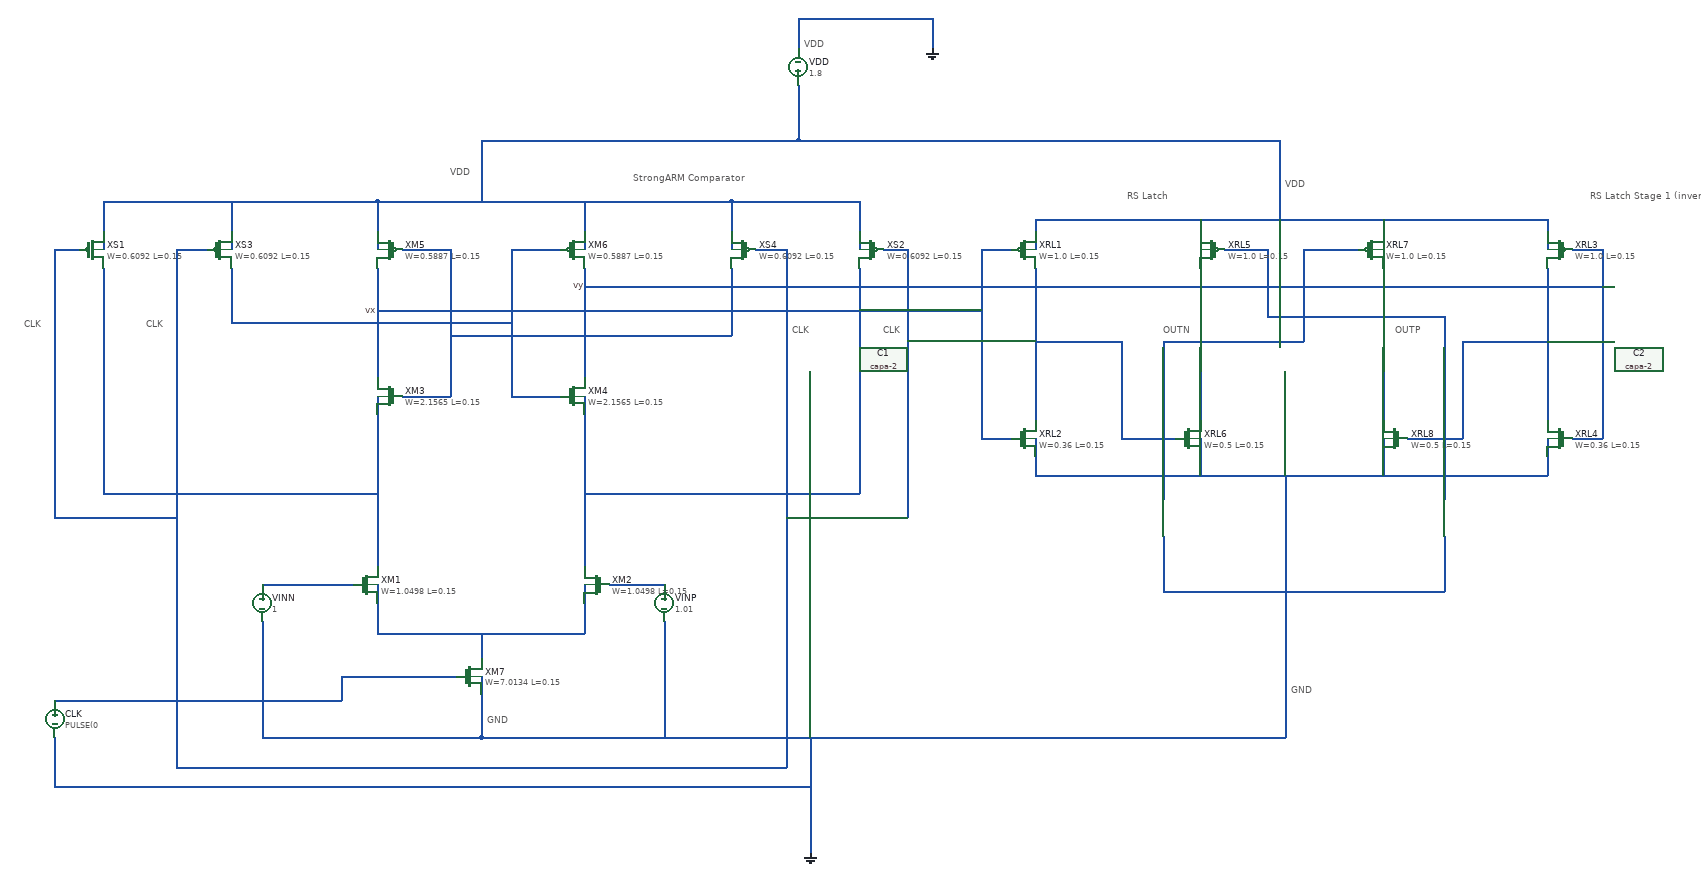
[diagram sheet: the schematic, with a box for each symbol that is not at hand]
v {xschem version=3.4.7 file_version=1.2}
G {}
K {}
V {}
S {}
E {}
T {StrongARM Comparator} -2230 -1580 0 0 0.4 0.4 {}
T {RS Latch } -1420 -1550 0 0 0.3 0.3 {}
T {RS Latch Stage 1 (inverters)} -660 -1550 0 1 0.3 0.3 {}
T {OUTN} -1360 -1330 0 0 0.4 0.4 {}
T {OUTP
} -980 -1330 0 0 0.4 0.4 {}
T {VDD} -1160 -1570 0 0 0.4 0.4 {}
T {GND} -1150 -740 0 0 0.4 0.4 {}
T {GND} -2470 -690 0 0 0.4 0.4 {}
T {CLK} -1970 -1330 0 0 0.4 0.4 {}
T {VDD} -1950 -1800 0 0 0.4 0.4 {}
T {CLK} -1820 -1330 0 0 0.4 0.4 {}
T {CLK} -3030 -1340 0 0 0.4 0.4 {}
T {CLK} -3230 -1340 0 0 0.4 0.4 {}
T {VDD} -2530 -1590 0 0 0.4 0.4 {}
N -3100 -1500 -3100 -1480 {lab=#net1}
N -3160 -1450 -3140 -1450 {lab=#net2}
N -3100 -1420 -3100 -1400 {lab=#net3}
N -2890 -1500 -2890 -1480 {lab=#net1}
N -2950 -1450 -2930 -1450 {lab=#net2}
N -2890 -1420 -2890 -1400 {lab=vx}
N -2610 -1450 -2590 -1450 {lab=vy}
N -2650 -1420 -2650 -1400 {lab=vx}
N -2650 -1260 -2650 -1240 {lab=vx}
N -2610 -1210 -2590 -1210 {lab=vy}
N -2650 -1180 -2650 -1160 {lab=#net3}
N -2650 -950 -2650 -930 {lab=#net3}
N -2650 -870 -2650 -850 {lab=#net4}
N -2480 -800 -2480 -780 {lab=#net4}
N -2540 -750 -2520 -750 {lab=#net2}
N -2480 -720 -2480 -700 {lab=GND}
N -1570 -1500 -1570 -1480 {lab=#net1}
N -1630 -1450 -1610 -1450 {lab=vx}
N -1570 -1420 -1570 -1400 {lab=#net5}
N -1570 -1190 -1570 -1170 {lab=#net5}
N -1630 -1140 -1610 -1140 {lab=vx}
N -1570 -1110 -1570 -1090 {lab=GND}
N -1300 -1180 -1300 -1160 {lab=#net6}
N -1300 -1100 -1300 -1080 {lab=GND}
N -1300 -1430 -1300 -1180 {lab=#net6}
N -1570 -1400 -1570 -1190 {lab=#net5}
N -1660 -1450 -1630 -1450 {lab=vx}
N -1660 -1450 -1660 -1140 {lab=vx}
N -1660 -1140 -1630 -1140 {lab=vx}
N -1430 -1140 -1340 -1140 {lab=#net5}
N -1430 -1300 -1430 -1140 {lab=#net5}
N -730 -1500 -730 -1480 {lab=#net1}
N -690 -1450 -670 -1450 {lab=vy}
N -730 -1420 -730 -1400 {lab=#net7}
N -730 -1190 -730 -1170 {lab=#net7}
N -690 -1140 -670 -1140 {lab=vy}
N -730 -1110 -730 -1090 {lab=GND}
N -1000 -1180 -1000 -1160 {lab=#net8}
N -1000 -1100 -1000 -1080 {lab=GND}
N -1000 -1430 -1000 -1180 {lab=#net8}
N -730 -1400 -730 -1190 {lab=#net7}
N -670 -1450 -640 -1450 {lab=vy}
N -640 -1450 -640 -1140 {lab=vy}
N -670 -1140 -640 -1140 {lab=vy}
N -870 -1300 -730 -1300 {lab=#net7}
N -960 -1140 -870 -1140 {lab=#net7}
N -870 -1300 -870 -1140 {lab=#net7}
N -1130 -1450 -1040 -1450 {lab=#net6}
N -1130 -1450 -1130 -1300 {lab=#net6}
N -1300 -1300 -1130 -1300 {lab=#net6}
N -1260 -1450 -1190 -1450 {lab=#net8}
N -1190 -1450 -1190 -1340 {lab=#net8}
N -1190 -1340 -1000 -1340 {lab=#net8}
N -1570 -1500 -730 -1500 {lab=#net1}
N -1000 -1500 -1000 -1480 {lab=#net1}
N -1300 -1500 -1300 -1480 {lab=#net1}
N -1570 -1090 -1570 -1080 {lab=GND}
N -1570 -1080 -730 -1080 {lab=GND}
N -730 -1090 -730 -1080 {lab=GND}
N -1000 -1110 -1000 -1100 {lab=GND}
N -1300 -1110 -1300 -1100 {lab=GND}
N -1330 -1300 -1300 -1300 {lab=#net6}
N -1000 -1340 -980 -1340 {lab=#net8}
N -3100 -1530 -3100 -1500 {lab=#net1}
N -3100 -1530 -2650 -1530 {lab=#net1}
N -2650 -1530 -2650 -1490 {lab=#net1}
N -2890 -1530 -2890 -1500 {lab=#net1}
N -2650 -1400 -2650 -1260 {lab=vx}
N -2650 -1160 -2650 -950 {lab=#net3}
N -2980 -1450 -2950 -1450 {lab=#net2}
N -2980 -1450 -2980 -950 {lab=#net2}
N -3180 -1450 -3160 -1450 {lab=#net2}
N -3180 -1450 -3180 -1010 {lab=#net2}
N -3180 -1010 -2980 -1010 {lab=#net2}
N -3100 -1400 -3100 -1090 {lab=#net3}
N -3100 -1090 -3100 -1050 {lab=#net3}
N -3100 -1050 -2650 -1050 {lab=#net3}
N -2890 -1400 -2890 -1360 {lab=vx}
N -2590 -1450 -2530 -1450 {lab=vy}
N -2530 -1450 -2530 -1210 {lab=vy}
N -2590 -1210 -2530 -1210 {lab=vy}
N -1860 -1500 -1860 -1480 {lab=#net1}
N -1820 -1450 -1800 -1450 {lab=#net2}
N -1860 -1420 -1860 -1400 {lab=#net9}
N -2070 -1500 -2070 -1480 {lab=#net1}
N -2030 -1450 -2010 -1450 {lab=#net2}
N -2070 -1420 -2070 -1400 {lab=vy}
N -2370 -1450 -2350 -1450 {lab=vx}
N -2310 -1420 -2310 -1400 {lab=vy}
N -2310 -1260 -2310 -1240 {lab=vy}
N -2370 -1210 -2350 -1210 {lab=vx}
N -2310 -1180 -2310 -1160 {lab=#net9}
N -2310 -950 -2310 -930 {lab=#net9}
N -2310 -870 -2310 -850 {lab=#net4}
N -1860 -1530 -1860 -1500 {lab=#net1}
N -2310 -1530 -2310 -1490 {lab=#net1}
N -2070 -1530 -2070 -1500 {lab=#net1}
N -2310 -1400 -2310 -1260 {lab=vy}
N -2310 -1160 -2310 -950 {lab=#net9}
N -2010 -1450 -1980 -1450 {lab=#net2}
N -1980 -1450 -1980 -950 {lab=#net2}
N -1800 -1450 -1780 -1450 {lab=#net2}
N -1780 -1450 -1780 -1010 {lab=#net2}
N -1980 -1010 -1780 -1010 {lab=#net2}
N -1860 -1400 -1860 -1090 {lab=#net9}
N -1860 -1090 -1860 -1050 {lab=#net9}
N -2310 -1050 -1860 -1050 {lab=#net9}
N -2070 -1400 -2070 -1360 {lab=vy}
N -2430 -1450 -2370 -1450 {lab=vx}
N -2430 -1450 -2430 -1210 {lab=vx}
N -2430 -1210 -2370 -1210 {lab=vx}
N -2070 -1360 -2070 -1310 {lab=vy}
N -2650 -850 -2650 -820 {lab=#net4}
N -2650 -820 -2310 -820 {lab=#net4}
N -2310 -850 -2310 -820 {lab=#net4}
N -2480 -820 -2480 -800 {lab=#net4}
N -2480 -700 -2480 -650 {lab=GND}
N -2980 -950 -2980 -650 {lab=#net2}
N -2980 -650 -2980 -600 {lab=#net2}
N -2980 -600 -1980 -600 {lab=#net2}
N -1980 -950 -1980 -600 {lab=#net2}
N -2650 -1530 -2300 -1530 {lab=#net1}
N -1960 -1660 -1960 -1630 {lab=#net1}
N -2430 -1630 -1960 -1630 {lab=#net1}
N -2480 -1630 -2430 -1630 {lab=#net1}
N -2480 -1630 -2480 -1530 {lab=#net1}
N -1960 -1630 -1170 -1630 {lab=#net1}
N -1170 -1630 -1170 -1510 {lab=#net1}
N -1170 -1510 -1170 -1500 {lab=#net1}
N -2770 -900 -2690 -900 {lab=#net10}
N -2480 -650 -1320 -650 {lab=GND}
N -1320 -650 -1160 -650 {lab=GND}
N -1160 -1080 -1160 -650 {lab=GND}
N -1360 -1300 -1330 -1300 {lab=#net6}
N -1360 -1300 -1360 -1040 {lab=#net6}
N -980 -1340 -900 -1340 {lab=#net8}
N -900 -1340 -900 -1040 {lab=#net8}
N -900 -980 -900 -890 {lab=GND}
N -1160 -890 -900 -890 {lab=GND}
N -1360 -980 -1360 -890 {lab=GND}
N -1360 -890 -1160 -890 {lab=GND}
N -3180 -710 -2980 -710 {lab=#net2}
N -1940 -650 -1940 -460 {lab=GND}
N -1960 -1720 -1960 -1660 {lab=#net1}
N -1960 -1830 -1960 -1780 {lab=GND}
N -1960 -1830 -1740 -1830 {lab=GND}
N -1740 -1830 -1740 -1780 {lab=GND}
N -2840 -900 -2770 -900 {lab=#net10}
N -2180 -840 -2180 -650 {lab=GND}
N -2310 -1390 -2230 -1390 {lab=vy}
N -2230 -1390 -2080 -1390 {lab=vy}
N -2080 -1390 -640 -1390 {lab=vy}
N -2310 -1310 -2070 -1310 {lab=vy}
N -2350 -1310 -2310 -1310 {lab=vy}
N -2530 -1310 -2350 -1310 {lab=vy}
N -2890 -1360 -2890 -1330 {lab=vx}
N -2640 -1350 -2220 -1350 {lab=vx}
N -2650 -1350 -2640 -1350 {lab=vx}
N -2220 -1350 -1790 -1350 {lab=vx}
N -1790 -1350 -1660 -1350 {lab=vx}
N -1570 -1300 -1430 -1300 {lab=#net5}
N -3180 -650 -3180 -590 {lab=GND}
N -3180 -590 -3180 -570 {lab=GND}
N -3180 -570 -2070 -570 {lab=GND}
N -2070 -570 -1940 -570 {lab=GND}
N -2570 -750 -2540 -750 {lab=#net2}
N -2840 -840 -2840 -650 {lab=GND}
N -2840 -650 -2480 -650 {lab=GND}
N -2980 -710 -2710 -710 {lab=#net2}
N -2710 -750 -2710 -710 {lab=#net2}
N -2710 -750 -2570 -750 {lab=#net2}
N -2890 -1330 -2650 -1330 {lab=vx}
N -2650 -1330 -2480 -1330 {lab=vx}
N -2480 -1330 -2430 -1330 {lab=vx}
N -2480 -750 -2480 -730 {lab=GND}
N -2310 -900 -2310 -880 {lab=#net4}
N -2650 -900 -2650 -880 {lab=#net4}
N -2310 -1470 -2310 -1450 {lab=#net1}
N -2650 -1470 -2650 -1450 {lab=#net1}
N -2650 -1490 -2650 -1480 {lab=#net1}
N -2310 -1490 -2310 -1480 {lab=#net1}
N -2300 -1530 -2070 -1530 {lab=#net1}
N -2070 -1530 -1860 -1530 {lab=#net1}
N -2650 -1210 -2650 -1190 {lab=#net3}
N -2310 -1210 -2310 -1190 {lab=#net9}
N -2890 -1470 -2890 -1450 {lab=#net1}
N -3100 -1470 -3100 -1450 {lab=#net1}
N -2070 -1470 -2070 -1450 {lab=#net1}
N -1860 -1470 -1860 -1450 {lab=#net1}
N -1300 -1140 -1300 -1110 {lab=GND}
N -1000 -1140 -1000 -1110 {lab=GND}
N -730 -1140 -730 -1110 {lab=GND}
N -730 -1480 -730 -1450 {lab=#net1}
N -1000 -1480 -1000 -1450 {lab=#net1}
N -1570 -1480 -1570 -1450 {lab=#net1}
N -1300 -1480 -1300 -1450 {lab=#net1}
N -1570 -1140 -1570 -1110 {lab=GND}
N -2650 -880 -2650 -870 {lab=#net4}
N -2310 -880 -2310 -870 {lab=#net4}
N -2480 -730 -2480 -720 {lab=GND}
N -2310 -1190 -2310 -1180 {lab=#net9}
N -2650 -1190 -2650 -1180 {lab=#net3}
N -3100 -1480 -3100 -1470 {lab=#net1}
N -2890 -1480 -2890 -1470 {lab=#net1}
N -2650 -1480 -2650 -1470 {lab=#net1}
N -2310 -1480 -2310 -1470 {lab=#net1}
N -2070 -1480 -2070 -1470 {lab=#net1}
N -1860 -1480 -1860 -1470 {lab=#net1}
N -2270 -900 -2180 -900 {lab=#net11}
C {sky130_fd_pr/pfet_01v8.sym} -3120 -1450 0 0 {name=XS1 W=0.6092 L=0.15 nf=1 mult=1 model=pfet_01v8 spiceprefix=X ad="'int((nf+1)/2) * W/nf * 0.29'" pd="'2*int((nf+1)/2) * (W/nf + 0.29)'" as="'int((nf+2)/2) * W/nf * 0.29'" ps="'2*int((nf+2)/2) * (W/nf + 0.29)'" nrd="'0.29 / W'" nrs="'0.29 / W'" sa=0 sb=0 sd=0}
C {sky130_fd_pr/pfet_01v8.sym} -2910 -1450 0 0 {name=XS3 W=0.6092 L=0.15 nf=1 mult=1 model=pfet_01v8 spiceprefix=X ad="'int((nf+1)/2) * W/nf * 0.29'" pd="'2*int((nf+1)/2) * (W/nf + 0.29)'" as="'int((nf+2)/2) * W/nf * 0.29'" ps="'2*int((nf+2)/2) * (W/nf + 0.29)'" nrd="'0.29 / W'" nrs="'0.29 / W'" sa=0 sb=0 sd=0}
C {sky130_fd_pr/pfet_01v8.sym} -2630 -1450 0 1 {name=XM5 W=0.5887 L=0.15 nf=1 mult=1 model=pfet_01v8 spiceprefix=X ad="'int((nf+1)/2) * W/nf * 0.29'" pd="'2*int((nf+1)/2) * (W/nf + 0.29)'" as="'int((nf+2)/2) * W/nf * 0.29'" ps="'2*int((nf+2)/2) * (W/nf + 0.29)'" nrd="'0.29 / W'" nrs="'0.29 / W'" sa=0 sb=0 sd=0}
C {sky130_fd_pr/nfet_01v8.sym} -2630 -1210 0 1 {name=XM3 W=2.1565 L=0.15 nf=1 mult=1 model=nfet_01v8 spiceprefix=X ad="'int((nf+1)/2) * W/nf * 0.29'" pd="'2*int((nf+1)/2) * (W/nf + 0.29)'" as="'int((nf+2)/2) * W/nf * 0.29'" ps="'2*int((nf+2)/2) * (W/nf + 0.29)'" nrd="'0.29 / W'" nrs="'0.29 / W'" sa=0 sb=0 sd=0}
C {sky130_fd_pr/nfet_01v8.sym} -2670 -900 0 0 {name=XM1 W=1.0498 L=0.15 nf=1 mult=1 model=nfet_01v8 spiceprefix=X ad="'int((nf+1)/2) * W/nf * 0.29'" pd="'2*int((nf+1)/2) * (W/nf + 0.29)'" as="'int((nf+2)/2) * W/nf * 0.29'" ps="'2*int((nf+2)/2) * (W/nf + 0.29)'" nrd="'0.29 / W'" nrs="'0.29 / W'" sa=0 sb=0 sd=0}
C {sky130_fd_pr/nfet_01v8.sym} -2500 -750 0 0 {name=XM7 W=7.0134 L=0.15 nf=1 mult=1 model=nfet_01v8 spiceprefix=X ad="'int((nf+1)/2) * W/nf * 0.29'" pd="'2*int((nf+1)/2) * (W/nf + 0.29)'" as="'int((nf+2)/2) * W/nf * 0.29'" ps="'2*int((nf+2)/2) * (W/nf + 0.29)'" nrd="'0.29 / W'" nrs="'0.29 / W'" sa=0 sb=0 sd=0}
C {sky130_fd_pr/pfet_01v8.sym} -1590 -1450 0 0 {name=XRL1 W=1.0 L=0.15 nf=1 mult=1 model=pfet_01v8 spiceprefix=X ad="'int((nf+1)/2) * W/nf * 0.29'" pd="'2*int((nf+1)/2) * (W/nf + 0.29)'" as="'int((nf+2)/2) * W/nf * 0.29'" ps="'2*int((nf+2)/2) * (W/nf + 0.29)'" nrd="'0.29 / W'" nrs="'0.29 / W'" sa=0 sb=0 sd=0}
C {sky130_fd_pr/nfet_01v8.sym} -1590 -1140 0 0 {name=XRL2 W=0.36 L=0.15 nf=1 mult=1 model=nfet_01v8 spiceprefix=X ad="'int((nf+1)/2) * W/nf * 0.29'" pd="'2*int((nf+1)/2) * (W/nf + 0.29)'" as="'int((nf+2)/2) * W/nf * 0.29'" ps="'2*int((nf+2)/2) * (W/nf + 0.29)'" nrd="'0.29 / W'" nrs="'0.29 / W'" sa=0 sb=0 sd=0}
C {sky130_fd_pr/pfet_01v8.sym} -1280 -1450 0 1 {name=XRL5 W=1.0 L=0.15 nf=1 mult=1 model=pfet_01v8 spiceprefix=X ad="'int((nf+1)/2) * W/nf * 0.29'" pd="'2*int((nf+1)/2) * (W/nf + 0.29)'" as="'int((nf+2)/2) * W/nf * 0.29'" ps="'2*int((nf+2)/2) * (W/nf + 0.29)'" nrd="'0.29 / W'" nrs="'0.29 / W'" sa=0 sb=0 sd=0}
C {sky130_fd_pr/nfet_01v8.sym} -1320 -1140 0 0 {name=XRL6 W=0.5 L=0.15 nf=1 mult=1 model=nfet_01v8 spiceprefix=X ad="'int((nf+1)/2) * W/nf * 0.29'" pd="'2*int((nf+1)/2) * (W/nf + 0.29)'" as="'int((nf+2)/2) * W/nf * 0.29'" ps="'2*int((nf+2)/2) * (W/nf + 0.29)'" nrd="'0.29 / W'" nrs="'0.29 / W'" sa=0 sb=0 sd=0}
C {sky130_fd_pr/pfet_01v8.sym} -710 -1450 0 1 {name=XRL3 W=1.0 L=0.15 nf=1 mult=1 model=pfet_01v8 spiceprefix=X ad="'int((nf+1)/2) * W/nf * 0.29'" pd="'2*int((nf+1)/2) * (W/nf + 0.29)'" as="'int((nf+2)/2) * W/nf * 0.29'" ps="'2*int((nf+2)/2) * (W/nf + 0.29)'" nrd="'0.29 / W'" nrs="'0.29 / W'" sa=0 sb=0 sd=0}
C {sky130_fd_pr/nfet_01v8.sym} -710 -1140 0 1 {name=XRL4 W=0.36 L=0.15 nf=1 mult=1 model=nfet_01v8 spiceprefix=X ad="'int((nf+1)/2) * W/nf * 0.29'" pd="'2*int((nf+1)/2) * (W/nf + 0.29)'" as="'int((nf+2)/2) * W/nf * 0.29'" ps="'2*int((nf+2)/2) * (W/nf + 0.29)'" nrd="'0.29 / W'" nrs="'0.29 / W'" sa=0 sb=0 sd=0}
C {sky130_fd_pr/pfet_01v8.sym} -1020 -1450 0 0 {name=XRL7 W=1.0 L=0.15 nf=1 mult=1 model=pfet_01v8 spiceprefix=X ad="'int((nf+1)/2) * W/nf * 0.29'" pd="'2*int((nf+1)/2) * (W/nf + 0.29)'" as="'int((nf+2)/2) * W/nf * 0.29'" ps="'2*int((nf+2)/2) * (W/nf + 0.29)'" nrd="'0.29 / W'" nrs="'0.29 / W'" sa=0 sb=0 sd=0}
C {sky130_fd_pr/nfet_01v8.sym} -980 -1140 0 1 {name=XRL8 W=0.5 L=0.15 nf=1 mult=1 model=nfet_01v8 spiceprefix=X ad="'int((nf+1)/2) * W/nf * 0.29'" pd="'2*int((nf+1)/2) * (W/nf + 0.29)'" as="'int((nf+2)/2) * W/nf * 0.29'" ps="'2*int((nf+2)/2) * (W/nf + 0.29)'" nrd="'0.29 / W'" nrs="'0.29 / W'" sa=0 sb=0 sd=0}
C {sky130_fd_pr/pfet_01v8.sym} -1840 -1450 0 1 {name=XS2 W=0.6092 L=0.15 nf=1 mult=1 model=pfet_01v8 spiceprefix=X ad="'int((nf+1)/2) * W/nf * 0.29'" pd="'2*int((nf+1)/2) * (W/nf + 0.29)'" as="'int((nf+2)/2) * W/nf * 0.29'" ps="'2*int((nf+2)/2) * (W/nf + 0.29)'" nrd="'0.29 / W'" nrs="'0.29 / W'" sa=0 sb=0 sd=0}
C {sky130_fd_pr/pfet_01v8.sym} -2050 -1450 0 1 {name=XS4 W=0.6092 L=0.15 nf=1 mult=1 model=pfet_01v8 spiceprefix=X ad="'int((nf+1)/2) * W/nf * 0.29'" pd="'2*int((nf+1)/2) * (W/nf + 0.29)'" as="'int((nf+2)/2) * W/nf * 0.29'" ps="'2*int((nf+2)/2) * (W/nf + 0.29)'" nrd="'0.29 / W'" nrs="'0.29 / W'" sa=0 sb=0 sd=0}
C {sky130_fd_pr/pfet_01v8.sym} -2330 -1450 0 0 {name=XM6 W=0.5887 L=0.15 nf=1 mult=1 model=pfet_01v8 spiceprefix=X ad="'int((nf+1)/2) * W/nf * 0.29'" pd="'2*int((nf+1)/2) * (W/nf + 0.29)'" as="'int((nf+2)/2) * W/nf * 0.29'" ps="'2*int((nf+2)/2) * (W/nf + 0.29)'" nrd="'0.29 / W'" nrs="'0.29 / W'" sa=0 sb=0 sd=0}
C {sky130_fd_pr/nfet_01v8.sym} -2330 -1210 0 0 {name=XM4 W=2.1565 L=0.15 nf=1 mult=1 model=nfet_01v8 spiceprefix=X ad="'int((nf+1)/2) * W/nf * 0.29'" pd="'2*int((nf+1)/2) * (W/nf + 0.29)'" as="'int((nf+2)/2) * W/nf * 0.29'" ps="'2*int((nf+2)/2) * (W/nf + 0.29)'" nrd="'0.29 / W'" nrs="'0.29 / W'" sa=0 sb=0 sd=0}
C {sky130_fd_pr/nfet_01v8.sym} -2290 -900 0 1 {name=XM2 W=1.0498 L=0.15 nf=1 mult=1 model=nfet_01v8 spiceprefix=X ad="'int((nf+1)/2) * W/nf * 0.29'" pd="'2*int((nf+1)/2) * (W/nf + 0.29)'" as="'int((nf+2)/2) * W/nf * 0.29'" ps="'2*int((nf+2)/2) * (W/nf + 0.29)'" nrd="'0.29 / W'" nrs="'0.29 / W'" sa=0 sb=0 sd=0}
C {capa-2.sym} -1360 -1010 0 0 {name=C1
m=1
value=20f
footprint=1206
device=polarized_capacitor}
C {capa-2.sym} -900 -1010 0 0 {name=C2
m=1
value=20f
footprint=1206
device=polarized_capacitor}
C {vsource.sym} -3180 -680 0 0 {name=CLK value=PULSE(0 1.8 0 10p 10p 1n 2n) savecurrent=false}
C {gnd.sym} -1940 -460 0 0 {name=l1 lab=GND}
C {vsource.sym} -1960 -1750 2 0 {name=VDD value=1.8 savecurrent=false}
C {gnd.sym} -1740 -1780 0 0 {name=l2 lab=GND}
C {vsource.sym} -2840 -870 0 0 {name=VINN value=1 savecurrent=false}
C {vsource.sym} -2180 -870 0 0 {name=VINP value=1.01 savecurrent=false}
C {lab_wire.sym} -2650 -1350 0 0 {name=vx sig_type=std_logic lab=vx}
C {lab_wire.sym} -2310 -1390 0 0 {name=vy sig_type=std_logic lab=vy}
C {title.sym} -3110 -510 0 0 {name=l3 author="Bintang W"}
